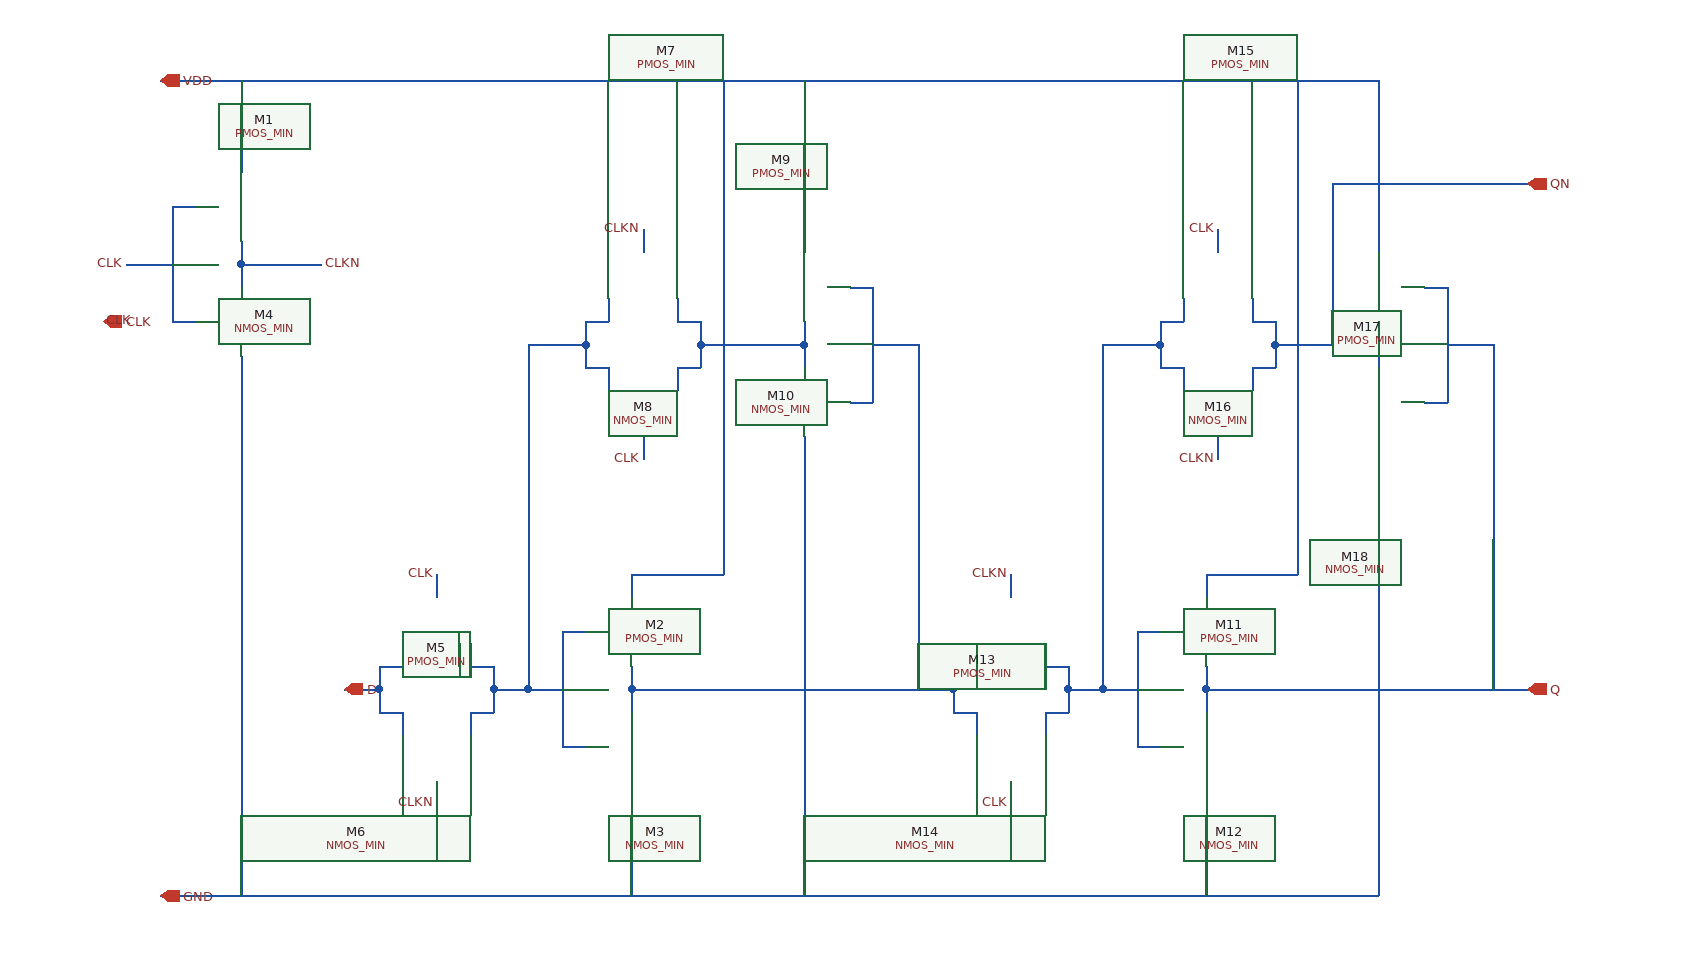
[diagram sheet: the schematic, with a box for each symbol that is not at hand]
v {xschem version=3.4.5 file_version=1.2
}
G {}
K {}
V {}
S {}
E {}
N 200 180 200 200 {
lab=CLKN}
N 200 200 270 200 {
lab=CLKN}
N 200 200 200 220 {
lab=CLKN}
N 140 150 160 150 {
lab=CLK}
N 140 150 140 250 {
lab=CLK}
N 140 250 160 250 {
lab=CLK}
N 200 280 200 300 {
lab=GND}
N 200 100 200 120 {
lab=VDD}
N 100 200 140 200 {
lab=CLK}
N 540 550 540 570 {
lab=#net1}
N 540 570 540 590 {
lab=#net1}
N 480 520 500 520 {
lab=#net2}
N 480 520 480 620 {
lab=#net2}
N 480 620 500 620 {
lab=#net2}
N 540 650 540 670 {
lab=GND}
N 540 470 540 490 {
lab=VDD}
N 400 530 400 550 {
lab=#net2}
N 400 550 420 550 {
lab=#net2}
N 420 550 420 570 {
lab=#net2}
N 400 590 400 610 {
lab=#net2}
N 400 590 420 590 {
lab=#net2}
N 420 570 420 590 {
lab=#net2}
N 420 570 450 570 {
lab=#net2}
N 340 590 340 610 {
lab=D}
N 320 590 340 590 {
lab=D}
N 320 570 320 590 {
lab=D}
N 320 550 320 570 {
lab=D}
N 320 550 340 550 {
lab=D}
N 340 530 340 550 {
lab=D}
N 290 570 320 570 {
lab=D}
N 370 470 370 490 {
lab=CLK}
N 370 470 370 490 {
lab=CLK}
N 370 650 370 670 {
lab=CLKN}
N 450 330 450 570 {
lab=#net2}
N 580 230 580 250 {
lab=#net3}
N 580 250 600 250 {
lab=#net3}
N 600 250 600 270 {
lab=#net3}
N 580 290 580 310 {
lab=#net3}
N 580 290 600 290 {
lab=#net3}
N 600 270 600 290 {
lab=#net3}
N 520 290 520 310 {
lab=#net2}
N 500 290 520 290 {
lab=#net2}
N 500 270 500 290 {
lab=#net2}
N 500 250 500 270 {
lab=#net2}
N 500 250 520 250 {
lab=#net2}
N 520 230 520 250 {
lab=#net2}
N 550 170 550 190 {
lab=CLKN}
N 550 170 550 190 {
lab=CLKN}
N 550 350 550 370 {
lab=CLK}
N 450 270 450 330 {
lab=#net2}
N 450 270 500 270 {
lab=#net2}
N 690 250 690 270 {
lab=#net3}
N 690 270 690 290 {
lab=#net3}
N 730 220 750 220 {
lab=#net1}
N 750 220 750 320 {
lab=#net1}
N 730 320 750 320 {
lab=#net1}
N 690 350 690 370 {
lab=GND}
N 690 170 690 190 {
lab=VDD}
N 750 270 790 270 {
lab=#net1}
N 600 270 690 270 {
lab=#net3}
N 620 570 820 570 {
lab=#net1}
N 790 270 790 570 {
lab=#net1}
N 1040 550 1040 570 {
lab=Q}
N 1040 570 1110 570 {
lab=Q}
N 1040 570 1040 590 {
lab=Q}
N 980 520 1000 520 {
lab=#net4}
N 980 520 980 620 {
lab=#net4}
N 980 620 1000 620 {
lab=#net4}
N 1040 650 1040 670 {
lab=GND}
N 1040 470 1040 490 {
lab=VDD}
N 900 530 900 550 {
lab=#net4}
N 900 550 920 550 {
lab=#net4}
N 920 550 920 570 {
lab=#net4}
N 900 590 900 610 {
lab=#net4}
N 900 590 920 590 {
lab=#net4}
N 920 570 920 590 {
lab=#net4}
N 920 570 950 570 {
lab=#net4}
N 840 590 840 610 {
lab=#net1}
N 820 590 840 590 {
lab=#net1}
N 820 570 820 590 {
lab=#net1}
N 820 550 820 570 {
lab=#net1}
N 820 550 840 550 {
lab=#net1}
N 840 530 840 550 {
lab=#net1}
N 870 470 870 490 {
lab=CLKN}
N 870 470 870 490 {
lab=CLKN}
N 870 650 870 670 {
lab=CLK}
N 950 330 950 570 {
lab=#net4}
N 1080 230 1080 250 {
lab=QN}
N 1080 250 1100 250 {
lab=QN}
N 1100 250 1100 270 {
lab=QN}
N 1080 290 1080 310 {
lab=QN}
N 1080 290 1100 290 {
lab=QN}
N 1100 270 1100 290 {
lab=QN}
N 1020 290 1020 310 {
lab=#net4}
N 1000 290 1020 290 {
lab=#net4}
N 1000 270 1000 290 {
lab=#net4}
N 1000 250 1000 270 {
lab=#net4}
N 1000 250 1020 250 {
lab=#net4}
N 1020 230 1020 250 {
lab=#net4}
N 1050 170 1050 190 {
lab=CLK}
N 1050 170 1050 190 {
lab=CLK}
N 1050 350 1050 370 {
lab=CLKN}
N 950 270 950 330 {
lab=#net4}
N 950 270 1000 270 {
lab=#net4}
N 1190 250 1190 270 {
lab=QN}
N 1190 270 1190 290 {
lab=QN}
N 1230 220 1250 220 {
lab=Q}
N 1250 220 1250 320 {
lab=Q}
N 1230 320 1250 320 {
lab=Q}
N 1190 350 1190 370 {
lab=GND}
N 1190 170 1190 190 {
lab=VDD}
N 1250 270 1290 270 {
lab=Q}
N 1100 270 1190 270 {
lab=QN}
N 1120 570 1320 570 {
lab=Q}
N 1290 270 1290 570 {
lab=Q}
N 130 40 1190 40 {
lab=VDD}
N 1190 40 1190 170 {
lab=VDD}
N 690 40 690 170 {
lab=VDD}
N 200 40 200 100 {
lab=VDD}
N 200 300 200 750 {
lab=GND}
N 1190 370 1190 750 {
lab=GND}
N 1050 750 1190 750 {
lab=GND}
N 690 370 690 750 {
lab=GND}
N 1040 670 1040 750 {
lab=GND}
N 1040 470 1110 470 {
lab=VDD}
N 1120 40 1120 470 {
lab=VDD}
N 550 470 610 470 {
lab=VDD}
N 610 470 620 470 {
lab=VDD}
N 620 40 620 470 {
lab=VDD}
N 130 750 1050 750 {
lab=GND}
N 1150 160 1150 270 {
lab=QN}
N 1210 130 1320 130 {
lab=QN}
N 390 530 390 550 {
lab=VDD}
N 540 470 550 470 {
lab=VDD}
N 450 570 480 570 {
lab=#net2}
N 540 570 620 570 {
lab=#net1}
N 540 670 540 750 {
lab=GND}
N 1110 470 1120 470 {
lab=VDD}
N 1110 570 1120 570 {
lab=Q}
N 950 570 980 570 {
lab=#net4}
N 1150 130 1150 160 {
lab=QN}
N 1150 130 1210 130 {}
C {PMOS_MIN.sym} 160 150 0 0 {name=M1 l=10.0U w=40.0U
}
C {NMOS_MIN.sym} 160 250 0 0 {name=M4 l=10.0U w=10.0U
}
C {iopin.sym} 1320 570 2 1 {name=p2 lab=Q
}
C {PMOS_MIN.sym} 500 520 0 0 {name=M2 l=10.0U w=40.0U
}
C {NMOS_MIN.sym} 500 620 0 0 {name=M3 l=10.0U w=10.0U
}
C {PMOS_MIN.sym} 370 490 1 0 {name=M5 l=10.0U w=40.0U
}
C {NMOS_MIN.sym} 370 650 3 0 {name=M6 l=10.0U w=10.0U
}
C {iopin.sym} 290 570 0 1 {name=p7 lab=D
}
C {PMOS_MIN.sym} 550 190 1 0 {name=M7 l=10.0U w=40.0U
}
C {NMOS_MIN.sym} 550 350 3 0 {name=M8 l=10.0U w=10.0U
}
C {PMOS_MIN.sym} 730 220 0 1 {name=M9 l=10.0U w=40.0U
}
C {NMOS_MIN.sym} 730 320 0 1 {name=M10 l=10.0U w=10.0U
}
C {PMOS_MIN.sym} 1000 520 0 0 {name=M11 l=10.0U w=40.0U
}
C {NMOS_MIN.sym} 1000 620 0 0 {name=M12 l=10.0U w=10.0U
}
C {PMOS_MIN.sym} 870 490 1 0 {name=M13 l=10.0U w=40.0U
}
C {NMOS_MIN.sym} 870 650 3 0 {name=M14 l=10.0U w=10.0U
}
C {PMOS_MIN.sym} 1050 190 1 0 {name=M15 l=10.0U w=40.0U
}
C {NMOS_MIN.sym} 1050 350 3 0 {name=M16 l=10.0U w=10.0U
}
C {PMOS_MIN.sym} 1230 220 0 1 {name=M17 l=10.0U w=40.0U
}
C {NMOS_MIN.sym} 1230 320 0 1 {name=M18 l=10.0U w=10.0U
}
C {lab_pin.sym} 270 200 2 0 {name=p4 sig_type=std_logic lab=CLKN}
C {lab_pin.sym} 550 170 1 0 {name=p11 sig_type=std_logic lab=CLKN}
C {lab_pin.sym} 1050 370 3 0 {name=p20 sig_type=std_logic lab=CLKN}
C {lab_pin.sym} 870 470 1 0 {name=p19 sig_type=std_logic lab=CLKN}
C {lab_pin.sym} 370 670 3 0 {name=p9 sig_type=std_logic lab=CLKN}
C {iopin.sym} 130 40 0 1 {name=p33 lab=VDD
}
C {iopin.sym} 80 250 0 1 {name=p1 lab=CLK
}
C {lab_pin.sym} 80 250 2 0 {name=p3 sig_type=std_logic lab=CLK}
C {lab_pin.sym} 100 200 0 0 {name=p10 sig_type=std_logic lab=CLK}
C {lab_pin.sym} 870 670 3 0 {name=p5 sig_type=std_logic lab=CLK}
C {lab_pin.sym} 550 370 3 0 {name=p6 sig_type=std_logic lab=CLK}
C {lab_pin.sym} 370 470 1 0 {name=p8 sig_type=std_logic lab=CLK}
C {lab_pin.sym} 1050 170 1 0 {name=p12 sig_type=std_logic lab=CLK}
C {iopin.sym} 130 750 0 1 {name=p13 lab=GND
}
C {iopin.sym} 1320 130 2 1 {name=p14 lab=QN
}
